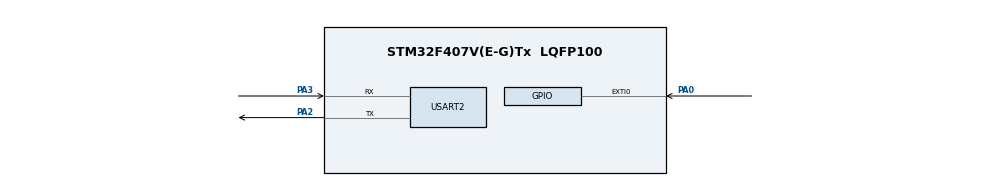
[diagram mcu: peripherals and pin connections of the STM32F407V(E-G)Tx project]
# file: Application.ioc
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Mcu.Family=STM32F4
Mcu.Name=STM32F407V(E-G)Tx
Mcu.Package=LQFP100
NVIC.EXTI0_IRQn=true\:0\:0\:false\:false\:true\:true\:true\:true
NVIC.PriorityGroup=NVIC_PRIORITYGROUP_4
PA0-WKUP.Signal=GPXTI0
PA2.Mode=Asynchronous
PA2.Signal=USART2_TX
PA3.Mode=Asynchronous
PA3.Signal=USART2_RX
PH0-OSC_IN.Mode=HSE-External-Oscillator
PH0-OSC_IN.Signal=RCC_OSC_IN
PH1-OSC_OUT.Mode=HSE-External-Oscillator
PH1-OSC_OUT.Signal=RCC_OSC_OUT
ProjectManager.HeapSize=0x200
ProjectManager.StackSize=0x400
ProjectManager.TargetToolchain=MDK-ARM V5.32
RCC.48MHZClocksFreq_Value=84000000
RCC.AHBFreq_Value=168000000
RCC.APB1CLKDivider=RCC_HCLK_DIV4
RCC.APB1Freq_Value=42000000
RCC.APB1TimFreq_Value=84000000
RCC.APB2CLKDivider=RCC_HCLK_DIV2
RCC.APB2Freq_Value=84000000
RCC.APB2TimFreq_Value=168000000
RCC.CortexFreq_Value=168000000
RCC.HCLKFreq_Value=168000000
RCC.HSE_VALUE=25000000
RCC.HSI_VALUE=16000000
RCC.LSE_VALUE=32768
RCC.PLLM=25
RCC.PLLN=336
RCC.PLLSourceVirtual=RCC_PLLSOURCE_HSE
RCC.SYSCLKFreq_VALUE=168000000
RCC.SYSCLKSource=RCC_SYSCLKSOURCE_PLLCLK
RCC.VCOOutputFreq_Value=336000000
USART2.VirtualMode=VM_ASYNC
board=custom

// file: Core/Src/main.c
/* USER CODE BEGIN Header */
/**
  ******************************************************************************
  * @file           : main.c
  * @brief          : Main program body
  ******************************************************************************
  * @attention
  *
  * <h2><center>&copy; Copyright (c) 2021 STMicroelectronics.
  * All rights reserved.</center></h2>
  *
  * This software component is licensed by ST under BSD 3-Clause license,
  * the "License"; You may not use this file except in compliance with the
  * License. You may obtain a copy of the License at:
  *                        opensource.org/licenses/BSD-3-Clause
  *
  ******************************************************************************
  */
/* USER CODE END Header */
#include "main.h"

void SystemClock_Config(void);

/* USER CODE BEGIN 0 */
uint8_t Messsage[] = "Application is running \r\n";
/* USER CODE END 0 */

int main(void)
{

  /* MCU Configuration--------------------------------------------------------*/

  /* Reset of all peripherals, Initializes the Flash interface and the Systick. */
  HAL_Init();

  /* Configure the system clock */
  SystemClock_Config();

  /* Initialize all configured peripherals */
  MX_GPIO_Init();
  MX_USART2_UART_Init();

  /* Infinite loop */
  while (1)
  {

    /* USER CODE BEGIN 3 */
		HAL_UART_Transmit(&huart2, (uint8_t *)Messsage, sizeof(Messsage), HAL_MAX_DELAY);
		HAL_Delay(500);
  }
  /* USER CODE END 3 */
}

void SystemClock_Config(void)
{
  RCC_OscInitTypeDef RCC_OscInitStruct = {0};
  RCC_ClkInitTypeDef RCC_ClkInitStruct = {0};

  /** Configure the main internal regulator output voltage
  */
  __HAL_RCC_PWR_CLK_ENABLE();
  __HAL_PWR_VOLTAGESCALING_CONFIG(PWR_REGULATOR_VOLTAGE_SCALE1);
  /** Initializes the RCC Oscillators according to the specified parameters
  * in the RCC_OscInitTypeDef structure.
  */
  RCC_OscInitStruct.OscillatorType = RCC_OSCILLATORTYPE_HSE;
  RCC_OscInitStruct.HSEState = RCC_HSE_ON;
  RCC_OscInitStruct.PLL.PLLState = RCC_PLL_ON;
  RCC_OscInitStruct.PLL.PLLSource = RCC_PLLSOURCE_HSE;
  RCC_OscInitStruct.PLL.PLLM = 4;
  RCC_OscInitStruct.PLL.PLLN = 168;
  RCC_OscInitStruct.PLL.PLLP = RCC_PLLP_DIV2;
  RCC_OscInitStruct.PLL.PLLQ = 4;
  if (HAL_RCC_OscConfig(&RCC_OscInitStruct) != HAL_OK)
  {
    Error_Handler();
  }
  /** Initializes the CPU, AHB and APB buses clocks
  */
  RCC_ClkInitStruct.ClockType = RCC_CLOCKTYPE_HCLK|RCC_CLOCKTYPE_SYSCLK
                              |RCC_CLOCKTYPE_PCLK1|RCC_CLOCKTYPE_PCLK2;
  RCC_ClkInitStruct.SYSCLKSource = RCC_SYSCLKSOURCE_PLLCLK;
  RCC_ClkInitStruct.AHBCLKDivider = RCC_SYSCLK_DIV1;
  RCC_ClkInitStruct.APB1CLKDivider = RCC_HCLK_DIV4;
  RCC_ClkInitStruct.APB2CLKDivider = RCC_HCLK_DIV2;

  if (HAL_RCC_ClockConfig(&RCC_ClkInitStruct, FLASH_LATENCY_5) != HAL_OK)
  {
    Error_Handler();
  }
}

void Error_Handler(void)
{
  __disable_irq();
  while (1)
  {
  }
}

/************************ (C) COPYRIGHT STMicroelectronics *****END OF FILE****/
